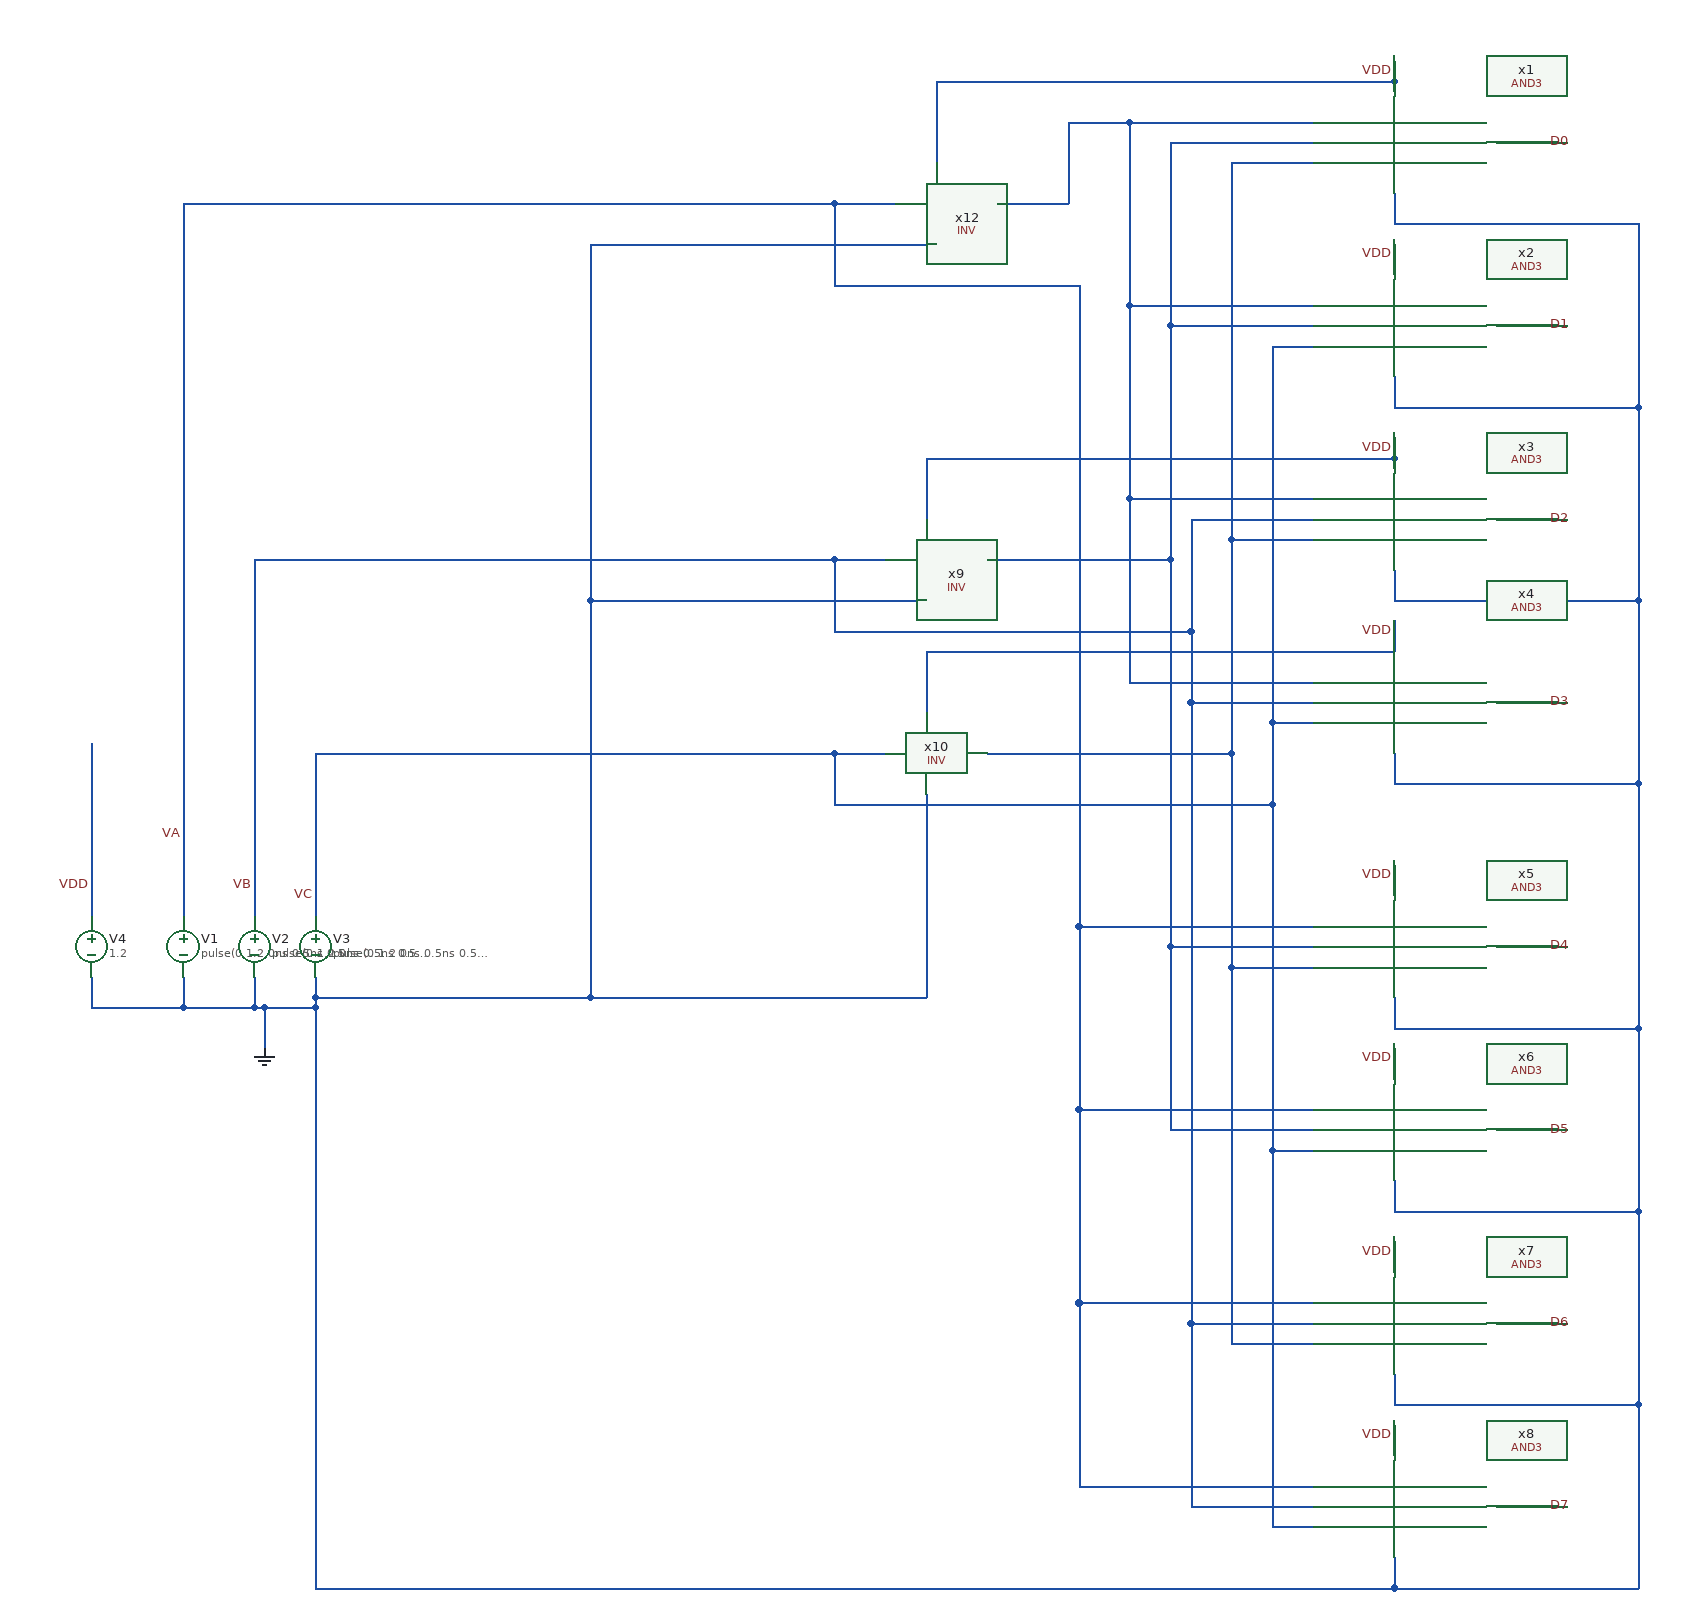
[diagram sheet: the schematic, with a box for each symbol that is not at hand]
v {xschem version=3.4.6 file_version=1.2}
G {}
K {}
V {}
S {}
E {}
N -1120 390 -1070 390 {lab=GND}
N -1200 390 -1130 390 {lab=GND}
N -1290 390 -1200 390 {lab=GND}
N -1130 390 -1120 390 {lab=GND}
N -10 -520 -10 -510 {lab=VDD}
N -10 -360 -10 -330 {lab=VDD}
N -10 -230 -10 -200 {lab=GND}
N -10 -410 -10 -380 {lab=GND}
N -10 -150 -10 -140 {lab=VDD}
N -10 10 -10 40 {lab=VDD}
N -10 140 -10 170 {lab=GND}
N -10 -40 -10 -10 {lab=GND}
N -10 250 -10 280 {lab=VDD}
N -10 430 -10 460 {lab=VDD}
N -10 560 -10 590 {lab=GND}
N -10 380 -10 410 {lab=GND}
N -10 620 -10 650 {lab=VDD}
N -10 800 -10 830 {lab=VDD}
N -10 930 -10 960 {lab=GND}
N -10 750 -10 780 {lab=GND}
N 90 -460 150 -460 {lab=D0}
N 90 -90 150 -90 {lab=D2}
N 90 90 150 90 {lab=D3}
N 90 330 150 330 {lab=D4}
N 90 -280 150 -280 {lab=D1}
N 90 510 150 510 {lab=D5}
N 90 700 150 700 {lab=D6}
N 90 880 150 880 {lab=D7}
N -1200 360 -1200 390 {lab=GND}
N -1070 380 -1070 390 {lab=GND}
N -1130 360 -1130 390 {lab=GND}
N -1290 360 -1290 390 {lab=GND}
N -1120 390 -1120 430 {lab=GND}
N -1290 130 -1290 300 {lab=VDD}
N -1200 -400 -1200 300 {lab=VA}
N -560 -400 -500 -400 {lab=VA}
N -1130 -50 -1130 300 {lab=VB}
N -1070 140 -1070 300 {lab=VC}
N -330 -480 -330 -400 {lab=#net1}
N -270 -480 -90 -480 {lab=#net1}
N -330 -480 -270 -480 {lab=#net1}
N -270 -480 -270 -300 {lab=#net1}
N -270 -300 -90 -300 {lab=#net1}
N -270 -300 -270 -110 {lab=#net1}
N -270 -110 -90 -110 {lab=#net1}
N -270 -110 -270 70 {lab=#net1}
N -270 70 -90 70 {lab=#net1}
N -560 -400 -560 -320 {lab=VA}
N -1200 -400 -560 -400 {lab=VA}
N -560 -320 -320 -320 {lab=VA}
N -320 310 -90 310 {lab=VA}
N -320 310 -320 490 {lab=VA}
N -320 490 -90 490 {lab=VA}
N -320 490 -320 680 {lab=VA}
N -320 680 -90 680 {lab=VA}
N -320 680 -320 860 {lab=VA}
N -320 860 -90 860 {lab=VA}
N -410 -50 -230 -50 {lab=#net2}
N -230 -280 -230 -50 {lab=#net2}
N -230 -460 -90 -460 {lab=#net2}
N -230 -280 -90 -280 {lab=#net2}
N -230 -460 -230 -280 {lab=#net2}
N -230 -50 -230 330 {lab=#net2}
N -230 330 -90 330 {lab=#net2}
N -230 330 -230 510 {lab=#net2}
N -230 510 -90 510 {lab=#net2}
N -560 -50 -560 20 {lab=VB}
N -1130 -50 -560 -50 {lab=VB}
N -560 20 -210 20 {lab=VB}
N -210 -90 -210 20 {lab=VB}
N -210 -90 -90 -90 {lab=VB}
N -210 20 -210 90 {lab=VB}
N -210 90 -90 90 {lab=VB}
N -210 90 -210 700 {lab=VB}
N -210 700 -90 700 {lab=VB}
N -210 700 -210 880 {lab=VB}
N -210 880 -90 880 {lab=VB}
N -410 140 -170 140 {lab=#net3}
N -170 -70 -170 140 {lab=#net3}
N -170 -440 -90 -440 {lab=#net3}
N -170 -70 -90 -70 {lab=#net3}
N -170 -440 -170 -70 {lab=#net3}
N -170 140 -170 350 {lab=#net3}
N -170 350 -90 350 {lab=#net3}
N -170 350 -170 720 {lab=#net3}
N -170 720 -90 720 {lab=#net3}
N -130 110 -130 190 {lab=VC}
N -130 110 -90 110 {lab=VC}
N -130 -260 -130 110 {lab=VC}
N -130 -260 -90 -260 {lab=VC}
N -130 190 -130 530 {lab=VC}
N -130 530 -90 530 {lab=VC}
N -130 530 -130 900 {lab=VC}
N -130 900 -90 900 {lab=VC}
N -10 780 230 780 {lab=GND}
N 230 780 230 960 {lab=GND}
N -10 960 230 960 {lab=GND}
N 230 590 230 780 {lab=GND}
N -10 -380 230 -380 {lab=GND}
N -10 -200 230 -200 {lab=GND}
N 230 -380 230 -200 {lab=GND}
N -10 -10 230 -10 {lab=GND}
N 230 -200 230 -10 {lab=GND}
N -10 170 230 170 {lab=GND}
N 230 -10 230 170 {lab=GND}
N -10 410 230 410 {lab=GND}
N 230 170 230 410 {lab=GND}
N -10 590 230 590 {lab=GND}
N 230 410 230 590 {lab=GND}
N -1070 960 -10 960 {lab=GND}
N -1070 390 -1070 960 {lab=GND}
N -400 -400 -330 -400 {lab=#net1}
N -560 -50 -510 -50 {lab=VB}
N -560 190 -130 190 {lab=VC}
N -560 140 -560 190 {lab=VC}
N -560 140 -510 140 {lab=VC}
N -1070 140 -560 140 {lab=VC}
N -320 -320 -320 310 {lab=VA}
N -470 180 -470 380 {lab=GND}
N -800 380 -470 380 {lab=GND}
N -1070 360 -1070 380 {lab=GND}
N -800 -10 -470 -10 {lab=GND}
N -1070 380 -800 380 {lab=GND}
N -800 -360 -460 -360 {lab=GND}
N -800 -10 -800 380 {lab=GND}
N -800 -360 -800 -10 {lab=GND}
N -460 -520 -460 -440 {lab=VDD}
N -460 -520 -10 -520 {lab=VDD}
N -10 -540 -10 -520 {lab=VDD}
N -470 -150 -470 -90 {lab=VDD}
N -470 -150 -10 -150 {lab=VDD}
N -10 -170 -10 -150 {lab=VDD}
N -470 40 -470 100 {lab=VDD}
N -470 40 -10 40 {lab=VDD}
C {vsource.sym} -1200 330 0 0 {name=V1 value="pulse(0 1.2 0ns 0.5ns 0.5ns 5ns 10ns)"}
C {vsource.sym} -1130 330 0 0 {name=V2 value="pulse(0 1.2 0ns 0.5ns 0.5ns 10ns 20ns)"}
C {vsource.sym} -1070 330 0 0 {name=V3 value="pulse(0 1.2 0ns 0.5ns 0.5ns 20ns 40ns)"}
C {vsource.sym} -1290 330 0 0 {name=V4 value=1.2 savecurrent=false}
C {lab_pin.sym} -1290 270 0 0 {name=p1 sig_type=std_logic lab=VDD}
C {lab_pin.sym} -1130 270 0 0 {name=p3 sig_type=std_logic lab=VB}
C {lab_pin.sym} -1070 280 0 0 {name=p4 sig_type=std_logic lab=VC}
C {gnd.sym} -1120 430 0 0 {name=l1 lab=GND}
C {/home/designer/shared/AND3.sym} -10 -460 0 0 {name=x1}
C {lab_wire.sym} 140 -460 0 1 {name=p5 sig_type=std_logic lab=D0}
C {lab_pin.sym} -1200 220 0 0 {name=p2 sig_type=std_logic lab=VA}
C {/home/designer/shared/AND3.sym} -10 -280 0 0 {name=x2}
C {lab_pin.sym} -10 -530 0 0 {name=p6 sig_type=std_logic lab=VDD}
C {lab_pin.sym} -10 -350 0 0 {name=p7 sig_type=std_logic lab=VDD}
C {/home/designer/shared/AND3.sym} -10 -90 0 0 {name=x3}
C {/home/designer/shared/AND3.sym} -10 90 0 0 {name=x4}
C {lab_pin.sym} -10 -160 0 0 {name=p11 sig_type=std_logic lab=VDD}
C {lab_pin.sym} -10 20 0 0 {name=p12 sig_type=std_logic lab=VDD}
C {/home/designer/shared/AND3.sym} -10 330 0 0 {name=x5}
C {/home/designer/shared/AND3.sym} -10 510 0 0 {name=x6}
C {lab_pin.sym} -10 260 0 0 {name=p15 sig_type=std_logic lab=VDD}
C {lab_pin.sym} -10 440 0 0 {name=p16 sig_type=std_logic lab=VDD}
C {/home/designer/shared/AND3.sym} -10 700 0 0 {name=x7}
C {/home/designer/shared/AND3.sym} -10 880 0 0 {name=x8}
C {lab_pin.sym} -10 630 0 0 {name=p19 sig_type=std_logic lab=VDD}
C {lab_pin.sym} -10 810 0 0 {name=p20 sig_type=std_logic lab=VDD}
C {lab_wire.sym} 140 -90 0 1 {name=p23 sig_type=std_logic lab=D2}
C {lab_wire.sym} 140 90 0 1 {name=p24 sig_type=std_logic lab=D3}
C {lab_wire.sym} 140 330 0 1 {name=p25 sig_type=std_logic lab=D4}
C {lab_wire.sym} 140 -280 0 1 {name=p26 sig_type=std_logic lab=D1}
C {lab_wire.sym} 140 510 0 1 {name=p27 sig_type=std_logic lab=D5}
C {lab_wire.sym} 140 700 0 1 {name=p28 sig_type=std_logic lab=D6}
C {lab_wire.sym} 140 880 0 1 {name=p29 sig_type=std_logic lab=D7}
C {/home/designer/shared/INV.sym} -450 -400 0 0 {name=x12}
C {/home/designer/shared/INV.sym} -460 -50 0 0 {name=x9}
C {/home/designer/shared/INV.sym} -460 140 0 0 {name=x10}
